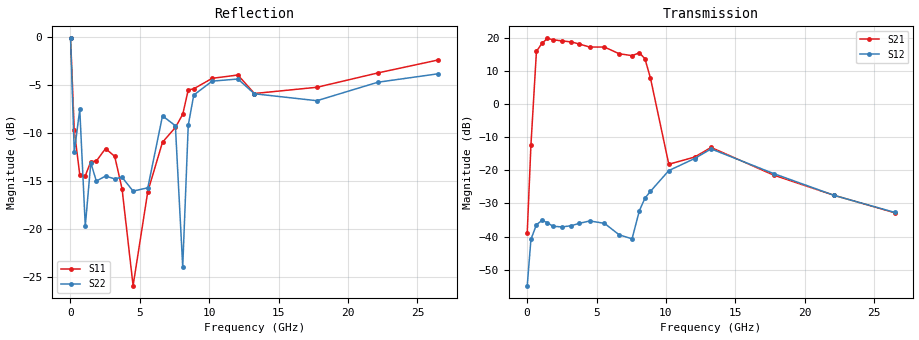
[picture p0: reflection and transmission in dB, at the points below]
!Agilent Technologies,N5242A,MY52422126,A.09.90.01
!Agilent N5242A: A.09.90.01
!Date: Wednesday, November 18, 2015 22:18:31
!Correction: S11(Full 2 Port(1,2))
!S21(Full 2 Port(1,2))
!S12(Full 2 Port(1,2))
!S22(Full 2 Port(1,2))
!S2P File: Measurements: S11, S21, S12, S22:
# Hz S  dB  R 50
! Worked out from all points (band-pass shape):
!   201 points, 10 MHz to 26.5 GHz, reference 50 ohm
!   highest |S21| = 19.92 dB at 1.467 GHz (marker M1); lowest = -38.8 dB at 10 MHz (marker M2)
!   |S21| within 3 dB of the highest: 754 MHz to 5.851 GHz (5.097 GHz wide, 154 % of centre)
!   lowest |S11| = -25.9 dB at 4.513 GHz (marker M3), VSWR 1.11, Z = 53.5 - j3.95 ohm
!   |S11| at or under -10 dB: 287.2 MHz to 6.987 GHz (6.7 GHz wide, 184 % of centre)
!   |S22| runs from -23.9 to -0.1 dB; largest |S21 - S12| = 9.9
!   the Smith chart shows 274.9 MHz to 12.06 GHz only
!   S11 on the Smith chart (normalised r, x): 274.9 MHz: 0.56, -0.27; 672.2 MHz: 1.14, +0.39; 3.719 GHz: 0.97, -0.32; 8.089 GHz: 0.98, -0.86; 10.21 GHz: 0.29, -0.46; 12.06 GHz: 0.22, +0.01
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1e7  -0.10 -6.9  -38.82 43.2  -54.85 20.6  -0.10 -6.3
2.749e8  -9.67 -138.5  -12.40 -123.0  -40.87 -71.1  -11.99 -153.0
6.7225e8  -14.34 59.6  15.97 110.7  -36.41 125.0  -7.50 -27.6
1.0696e9  -14.43 33.8  18.42 14.0  -35.13 31.7  -19.69 -10.8
1.46695e9  -12.96 4.0  19.92 -46.2  -35.79 -22.6  -13.06 -26.5
1.8643e9  -12.90 -5.2  19.50 -96.6  -36.90 -51.7  -14.98 -32.5
2.52655e9  -11.59 -31.8  19.15 -163.1  -37.08 -96.2  -14.46 -41.6
3.1888e9  -12.40 -64.5  18.84 134.5  -36.72 -141.8  -14.75 -52.0
3.7186e9  -15.79 -85.2  18.26 86.3  -36.04 -179.2  -14.58 -58.1
4.5133e9  -25.89 -46.6  17.29 20.4  -35.28 125.8  -16.03 -81.0
5.5729e9  -16.07 -33.5  17.29 -74.2  -36.00 58.3  -15.68 -20.4
6.6325e9  -10.93 -45.0  15.27 -173.3  -39.47 22.3  -8.18 -66.3
7.55965e9  -9.39 -66.4  14.70 102.2  -40.69 59.4  -9.21 -115.4
8.08945e9  -8.02 -68.0  15.54 36.4  -32.17 62.5  -23.93 -129.6
8.4868e9  -5.48 -81.9  13.78 -32.8  -28.41 37.6  -9.16 -45.1
8.88415e9  -5.36 -99.7  7.95 -92.5  -26.33 19.5  -6.01 -80.1
1.020865e10  -4.27 -127.8  -18.14 171.8  -20.05 -48.4  -4.56 -122.7
1.206295e10  -3.92 179.1  -15.97 -141.1  -16.42 -135.6  -4.34 -177.7
1.3255e10  -5.85 150.4  -13.06 158.3  -13.49 162.8  -5.88 155.5
1.77583e10  -5.20 44.2  -21.41 -67.5  -20.95 -64.8  -6.60 44.6
2.212915e10  -3.71 -87.3  -27.55 153.3  -27.56 150.9  -4.68 -90.8
2.65e10  -2.35 -165.5  -32.82 47.2  -32.71 42.7  -3.79 -143.7
